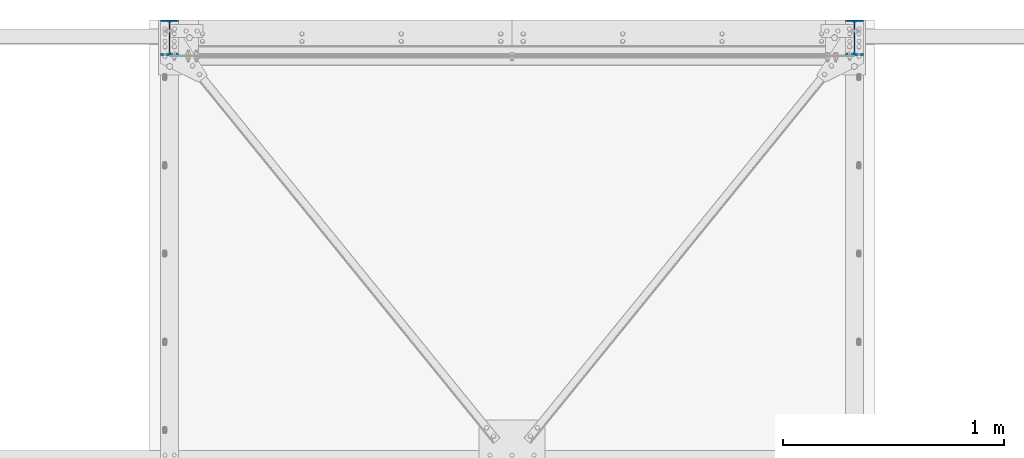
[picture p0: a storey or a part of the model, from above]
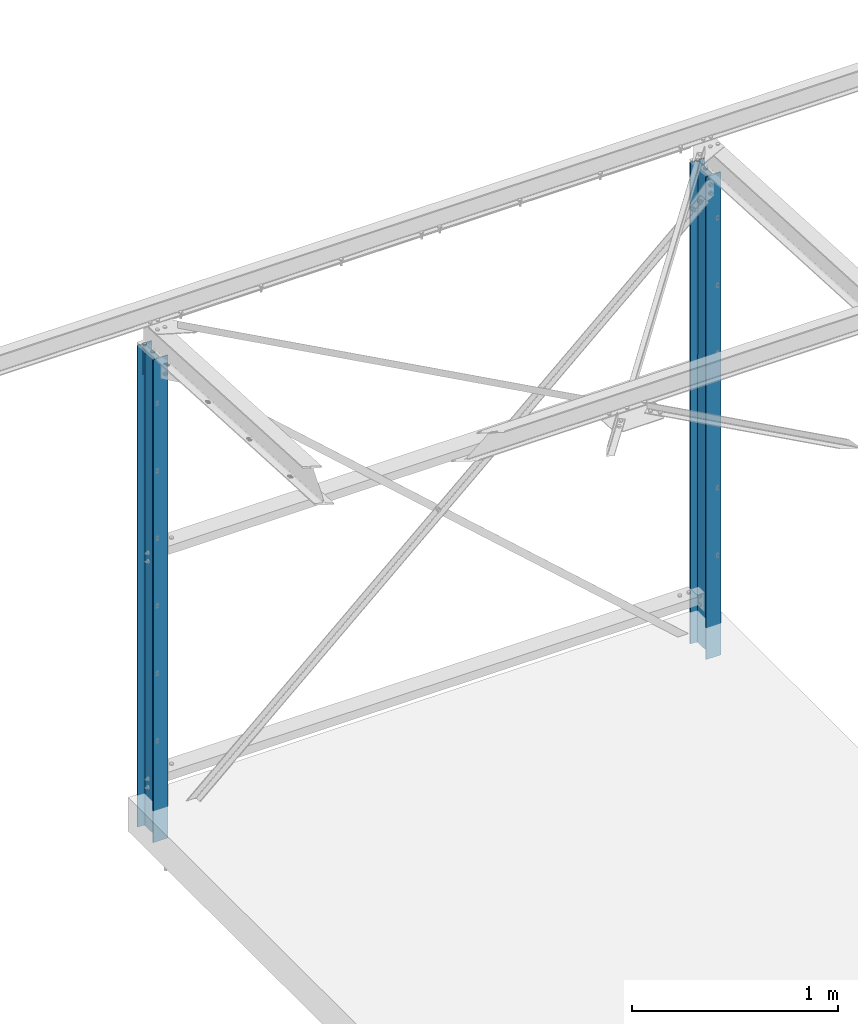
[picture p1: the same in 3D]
Properties of the parts of a building model (IFC2X3)

# File
Description: ViewDefinition[CoordinationView_V2.0, QuantityTakeOffAddOnView], Option [BaseQuantities:On], Option [GridExport:Off], Option [Assemblies:On], Option [Bolts:On], Option [Rebars:On], Option [PourObjects:Off], Option [Welds:Off], Option [SurfaceTreatments:Off], Option [LocationBy:0], Option [ViewColors:On], Option [SectionedSpine:Off], Option [PropertySets:On], Option [Export all:Off]
File name: preau_poleaero.ifc
Time: 2021-06-01T16:35:58
Author: PORTCM01\professeur
Organization: Structural Designer
Written by: IFC Database Version: Work
Made in: Tekla Structures Educational 2019, IFC Export Version: 4.0.0.0 Mar 7 2019

# IfcSite, Undefined
RefElevation: 0 mm

# IfcBuildingStorey, Undefined
In: Undefined
Elevation: 0 mm

# IfcBeam: 4550*200 (2)
In: Undefined
Description: 4550*200; Material: CONCRETE/C25/30
Tekla Commun - Phase: 1; Profil: 4550*200; Nom: POUTRE; sets with these values: 2
Tekla Quantités - Hauteur: 4550 mm; Largeur: 200 mm; sets with these values: 2
Pset_BeamCommon - LoadBearing: no
Name | Repère de pièce = Repère d'assemblage = Reference | Poids (kg) = NetWeight (kg) | Volume (m3) | Surface supérieure totale (m2) | Surface par tonne (m2) | Surface nette (m2) | Longueur (mm) | Length (mm) | OuterSurfaceArea (m2) | NetVolume (m3)
POUTRE | Po5 | 29791.9 | 12.4 | 2.7 | 4.4 | 131.7 | 13733.4 | 13733.4 | 131.739 | 12.4133
POUTRE | Po4 | 20476.6 | 8.5 | 1.9 | 4.5 | 91.2 | 9478.7 | 9478.66 | 91.2034 | 8.53192

# IfcBeam: 8550*200 (4)
In: Undefined
Description: 8550*200; Material: CONCRETE/C25/30
Tekla Commun - Phase: 1; Profil: 8550*200; Nom: POUTRE; sets with these values: 2
Tekla Quantités - Surface par tonne: 4.4 m2; Hauteur: 8550 mm; Largeur: 200 mm; sets with these values: 2
Pset_BeamCommon - LoadBearing: no
Name | Repère de pièce = Repère d'assemblage = Reference | Poids (kg) = NetWeight (kg) | Volume (m3) | Surface supérieure totale (m2) | Surface nette (m2) | Longueur (mm) = Length (mm) | OuterSurfaceArea (m2) | NetVolume (m3)
POUTRE | Po7 | 37962 | 15.8 | 1.9 | 165.3 | 9250 | 165.295 | 15.8175
POUTRE | Po6 | 38372.4 | 16 | 1.9 | 167.8 | 9450 | 167.753 | 15.9885
POUTRE | Po3 | 124128 | 51.7 | 6.9 | 547.8 | 34778 | 547.813 | 51.7201
POUTRE | Po2 | 38782.8 | 16.2 | 1.9 | 170.2 | 9650 | 170.212 | 16.1595

# IfcBeam: IPE120 (3)
In: Undefined
Description: IPE120; Material: Undefined/S275-E28
Tekla Commun - Finition: GALVA; Phase: 2; Profil: IPE120; Nom: PANNE; sets with these values: 2
Tekla Quantités - Poids: 0 kg; Volume: 0 m3; Surface supérieure totale: 0 m2; Surface par tonne: 0 m2; Surface nette: 5.2 m2; Hauteur: 120 mm; Largeur: 64 mm; Longueur: 10758 mm; sets with these values: 2
Pset_BeamCommon - LoadBearing: no
BaseQuantities - Length: 10758 mm; OuterSurfaceArea: 5.11005 m2; NetVolume: 0.0137591 m3; NetWeight: 0 kg
Name | Repère de pièce = Repère d'assemblage = Reference
PANNE | PN37
PANNE | PN36
PANNE | PN11

# IfcBeam: IPE160 (4)
In: Undefined
Description: IPE160; Material: Undefined/S275-E28
Tekla Commun - Finition: GALVA; Phase: 2; Profil: IPE160; Nom: TRAVERSE; sets with these values: 2
Tekla Quantités - Poids: 0 kg; Volume: 0 m3; Surface supérieure totale: 0 m2; Surface par tonne: 0 m2; Surface nette: 2.6 m2; Hauteur: 160 mm; Largeur: 82 mm; Longueur: 4043.9 mm; sets with these values: 2
Pset_BeamCommon - LoadBearing: no
BaseQuantities - Length: 4043.91 mm; OuterSurfaceArea: 2.51935 m2; NetVolume: 0.0078273 m3; NetWeight: 0 kg
Name | Repère de pièce = Repère d'assemblage = Reference
2 x TRAVERSE | T8
TRAVERSE | T6
TRAVERSE | T9

# IfcBeam: L40*4 (4)
In: Undefined
Description: L40*4; Material: Undefined/S235-E24
Tekla Commun - Finition: GALVA; Repère de pièce: S15; Repère d'assemblage: S15; Phase: 2; Profil: L40*4; Nom: STABILITE CVT; sets with these values: 2
Tekla Quantités - Poids: 0 kg; Volume: 0 m3; Surface supérieure totale: 0 m2; Surface par tonne: 0 m2; Surface nette: 0.4 m2; Hauteur: 40 mm; Largeur: 40 mm; Longueur: 2209.6 mm; sets with these values: 2
Pset_BeamCommon - LoadBearing: no; Reference: S15
BaseQuantities - Length: 2209.65 mm; OuterSurfaceArea: 0.342495 m2; NetVolume: 0.000672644 m3; NetWeight: 0 kg

# IfcBeam: PL1*20000 (2)
In: Undefined
Description: PL1*20000; Material: Undefined/S235-E24
Tekla Commun - Repère de pièce: X1; Repère d'assemblage: X1; Phase: 2; Profil: PL1*20000; Nom: BAVETTE; sets with these values: 2
Tekla Quantités - Poids: 0 kg; Volume: 0 m3; Surface supérieure totale: 0 m2; Surface par tonne: 0 m2; Surface nette: 7 m2; Hauteur: 20000 mm; Largeur: 1 mm; Longueur: 167.9 mm; sets with these values: 2
Pset_BeamCommon - LoadBearing: no; Reference: X1
BaseQuantities - Length: 167.904 mm; OuterSurfaceArea: 7.03146 m2; NetVolume: 0.00349555 m3; NetWeight: 0 kg

# IfcBeam: PL10*141 (2)
In: Undefined
Description: PL10*141; Material: Undefined/S235-E24
Tekla Commun - Finition: GALVA; Repère de pièce: 496; Repère d'assemblage: G11; Phase: 2; Profil: PL10*141; Nom: GOUSSET; sets with these values: 2
Tekla Quantités - Poids: 0 kg; Volume: 0 m3; Surface supérieure totale: 0 m2; Surface par tonne: 0 m2; Surface nette: 0.2 m2; Hauteur: 141.2 mm; Largeur: 10 mm; Longueur: 732.8 mm; sets with these values: 2
Pset_BeamCommon - LoadBearing: no; Reference: 496
BaseQuantities - Length: 732.76 mm; OuterSurfaceArea: 0.167426 m2; NetVolume: 0.000757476 m3; NetWeight: 0 kg

# IfcBeam: PL10*160 (6)
In: Undefined
Description: PL10*160; Material: Undefined/S275-E28
Tekla Commun - Finition: GALVA; Repère de pièce: 500; Phase: 2; Profil: PL10*160; Nom: PLATINE; sets with these values: 2
Tekla Quantités - Poids: 0 kg; Volume: 0 m3; Surface supérieure totale: 0 m2; Surface par tonne: 0 m2; Surface nette: 0.1 m2; Hauteur: 160 mm; Largeur: 10 mm; Longueur: 250 mm; sets with these values: 2
Pset_BeamCommon - LoadBearing: no; Reference: 500
BaseQuantities - Length: 250 mm; OuterSurfaceArea: 0.0882 m2; NetVolume: 0.0004 m3; NetWeight: 0 kg
Name | Repère d'assemblage
4 x PLATINE | G29
2 x PLATINE | G28

# IfcBeam: PL10*360 (4)
In: Undefined
Description: PL10*360; Material: Undefined/S235-E24
Tekla Commun - Finition: GALVA; Repère de pièce: 499; Repère d'assemblage: G29; Phase: 2; Profil: PL10*360; Nom: GOUSSET; sets with these values: 2
Tekla Quantités - Poids: 0 kg; Volume: 0 m3; Surface supérieure totale: 0 m2; Surface par tonne: 0 m2; Surface nette: 0.1 m2; Hauteur: 360 mm; Largeur: 10 mm; Longueur: 237.4 mm; sets with these values: 2
Pset_BeamCommon - LoadBearing: no; Reference: 499
BaseQuantities - Length: 237.448 mm; OuterSurfaceArea: 0.115218 m2; NetVolume: 0.000519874 m3; NetWeight: 0 kg

# IfcBeam: PL10*370 (2)
In: Undefined
Description: PL10*370; Material: Undefined/S235-E24
Tekla Commun - Finition: GALVA; Repère de pièce: 497; Repère d'assemblage: G28; Phase: 2; Profil: PL10*370; Nom: GOUSSET; sets with these values: 2
Tekla Quantités - Poids: 0 kg; Volume: 0 m3; Surface supérieure totale: 0 m2; Surface par tonne: 0 m2; Surface nette: 0.1 m2; Hauteur: 370 mm; Largeur: 10 mm; Longueur: 309.4 mm; sets with these values: 2
Pset_BeamCommon - LoadBearing: no; Reference: 497
BaseQuantities - Length: 309.388 mm; OuterSurfaceArea: 0.14183 m2; NetVolume: 0.000653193 m3; NetWeight: 0 kg

# IfcBeam: PL10*80 (4)
In: Undefined
Description: PL10*80; Material: Undefined/S235-E24
Tekla Commun - Finition: GALVA; Repère de pièce: 498; Repère d'assemblage: B14; Phase: 2; Profil: PL10*80; Nom: GOUSSET; sets with these values: 2
Tekla Quantités - Poids: 0 kg; Volume: 0 m3; Surface supérieure totale: 0 m2; Surface par tonne: 0 m2; Surface nette: 0 m2; Hauteur: 80 mm; Largeur: 10 mm; Longueur: 260 mm; sets with these values: 2
Pset_BeamCommon - LoadBearing: no; Reference: 498
BaseQuantities - Length: 260 mm; OuterSurfaceArea: 0.0466612 m2; NetVolume: 0.00020103 m3; NetWeight: 0 kg

# IfcBeam: PL10*82 (4)
In: Undefined
Description: PL10*82
Tekla Commun - Finition: GALVA; Phase: 2; Profil: PL10*82; sets with these values: 2
Tekla Quantités - Poids: 0 kg; Volume: 0 m3; Surface supérieure totale: 0 m2; Surface par tonne: 0 m2; Hauteur: 82 mm; Largeur: 10 mm; sets with these values: 2
Pset_BeamCommon - LoadBearing: no
BaseQuantities - NetWeight: 0 kg
Name | Material | Repère de pièce = Reference | Repère d'assemblage | Nom | Surface nette (m2) | Longueur (mm) | Length (mm) | OuterSurfaceArea (m2) | NetVolume (m3)
PLAT | Undefined/S235-E24 | 502 | PT11 | PLAT | 0 | 150 | 149.999 | 0.0297919 | 0.000125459
PLAT | Undefined/S235-E24 | 502 | PT13 | PLAT | 0 | 150 | 149.999 | 0.0297919 | 0.000125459
2 x PLATINE | Undefined/S275-E28 | 501 | G11 | PLATINE | 0.1 | 300 | 300 | 0.05684 | 0.000246

# IfcBeam: PL3*1450 (2)
In: Undefined
Description: PL3*1450; Material: Undefined/S235-E24
Tekla Commun - Finition: GALVA; Repère de pièce: F18; Repère d'assemblage: F18; Phase: 2; Profil: PL3*1450; Nom: FEUILLURE; sets with these values: 2
Tekla Quantités - Poids: 0 kg; Volume: 0 m3; Surface supérieure totale: 0 m2; Surface par tonne: 0 m2; Surface nette: 0.5 m2; Hauteur: 1450 mm; Largeur: 3 mm; Longueur: 159.3 mm; sets with these values: 2
Pset_BeamCommon - LoadBearing: no; Reference: F18
BaseQuantities - Length: 159.306 mm; OuterSurfaceArea: 0.479917 m2; NetVolume: 0.000705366 m3; NetWeight: 0 kg

# IfcBeam: PL5*157 (4)
In: Undefined
Description: PL5*157; Material: Undefined/S235-E24
Tekla Commun - Finition: GALVA; Repère de pièce: G32; Repère d'assemblage: G32; Phase: 2; Profil: PL5*157; Nom: GOUSSET; sets with these values: 2
Tekla Quantités - Poids: 0 kg; Volume: 0 m3; Surface supérieure totale: 0 m2; Surface par tonne: 0 m2; Surface nette: 0 m2; Hauteur: 156.7 mm; Largeur: 5 mm; Longueur: 169 mm; sets with these values: 2
Pset_BeamCommon - LoadBearing: no; Reference: G32
BaseQuantities - Length: 168.971 mm; NetWeight: 0 kg
Name | OuterSurfaceArea (m2) | NetVolume (m3)
GOUSSET | 0.0305038 | 0.000069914
GOUSSET | 0.030501 | 0.0000699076
2 x GOUSSET | 0.0305038 | 0.0000699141

# IfcBeam: PL5*211 (4)
In: Undefined
Description: PL5*211; Material: Undefined/S235-E24
Tekla Commun - Finition: GALVA; Repère de pièce: G30; Repère d'assemblage: G30; Phase: 2; Profil: PL5*211; Nom: GOUSSET; sets with these values: 2
Tekla Quantités - Poids: 0 kg; Volume: 0 m3; Surface supérieure totale: 0 m2; Surface par tonne: 0 m2; Surface nette: 0.1 m2; Hauteur: 211.5 mm; Largeur: 5 mm; Longueur: 235.8 mm; sets with these values: 2
Pset_BeamCommon - LoadBearing: no; Reference: G30
BaseQuantities - NetVolume: 0.000143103 m3; NetWeight: 0 kg
Name | Length (mm) | OuterSurfaceArea (m2)
GOUSSET | 235.796 | 0.0608244
GOUSSET | 235.796 | 0.0608243
2 x GOUSSET | 235.797 | 0.0608245

# IfcBeam: PL5*300, GOUSSET
In: Undefined
Description: PL5*300; Material: Undefined/S235-E24
Tekla Commun - Finition: GALVA; Repère de pièce: G31; Repère d'assemblage: G31; Phase: 2; Profil: PL5*300; Nom: GOUSSET; sets with these values: 2
Tekla Quantités - Poids: 0 kg; Volume: 0 m3; Surface supérieure totale: 0 m2; Surface par tonne: 0 m2; Surface nette: 0.2 m2; Hauteur: 300.3 mm; Largeur: 5 mm; Longueur: 353.7 mm; sets with these values: 2
Pset_BeamCommon - LoadBearing: no; Reference: G31
BaseQuantities - Length: 353.658 mm; OuterSurfaceArea: 0.213616 m2; NetVolume: 0.000518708 m3; NetWeight: 0 kg

# IfcBeam: PL5*60 (4)
In: Undefined
Description: PL5*60; Material: Undefined/S235-E24
Tekla Commun - Finition: GALVA; Repère de pièce: A16; Repère d'assemblage: A16; Phase: 2; Profil: PL5*60; Nom: ATTACHE; sets with these values: 2
Tekla Quantités - Poids: 0 kg; Volume: 0 m3; Surface supérieure totale: 0 m2; Surface par tonne: 0 m2; Surface nette: 0 m2; Hauteur: 60 mm; Largeur: 5 mm; Longueur: 247 mm; sets with these values: 2
Pset_BeamCommon - LoadBearing: no; Reference: A16
BaseQuantities - Length: 247 mm; OuterSurfaceArea: 0.03336 m2; NetVolume: 0.0000756 m3; NetWeight: 0 kg

# IfcBeam: TOLE10*180 (2)
In: Undefined
Description: TOLE10*180; Material: Undefined/S235-E24
Tekla Commun - Repère de pièce: 362; Phase: 2; Profil: TOLE10*180; Nom: PLATINE; sets with these values: 2
Tekla Quantités - Poids: 0 kg; Volume: 0 m3; Surface supérieure totale: 0 m2; Surface par tonne: 0 m2; Surface nette: 0.1 m2; Hauteur: 180 mm; Largeur: 10 mm; Longueur: 250 mm; sets with these values: 2
Pset_BeamCommon - LoadBearing: no; Reference: 362
BaseQuantities - Length: 250 mm; OuterSurfaceArea: 0.0909042 m2; NetVolume: 0.000414 m3; NetWeight: 0 kg
Name | Repère d'assemblage
PLATINE | PT13
PLATINE | PT11

# IfcBeam: UPF-100*50*4 (2)
In: Undefined
Description: UPF-100*50*4; Material: Undefined/S235-E24
Tekla Commun - Finition: GALVA; Repère de pièce: L31; Repère d'assemblage: L31; Phase: 2; Profil: UPF-100*50*4; Nom: LISSE; sets with these values: 2
Tekla Quantités - Poids: 0 kg; Volume: 0 m3; Surface supérieure totale: 0.3 m2; Surface par tonne: 0 m2; Surface nette: 1.2 m2; Hauteur: 100 mm; Largeur: 50 mm; Longueur: 3000 mm; sets with these values: 2
Pset_BeamCommon - LoadBearing: no; Reference: L31
BaseQuantities - Length: 3000 mm; OuterSurfaceArea: 1.17754 m2; NetVolume: 0.002304 m3; NetWeight: 0 kg

# IfcColumn: IPE160 (2)
In: Undefined
Description: IPE160; Material: Undefined/S275-E28
Tekla Commun - Finition: GALVA; Phase: 2; Profil: IPE160; Nom: POTEAU; sets with these values: 2
Tekla Quantités - Poids: 0 kg; Volume: 0 m3; Surface supérieure totale: 0 m2; Surface par tonne: 0 m2; Surface nette: 1.8 m2; Hauteur: 160 mm; Largeur: 82 mm; Longueur: 2862 mm; sets with these values: 2
Pset_ColumnCommon - LoadBearing: no
BaseQuantities - Length: 2861.96 mm; OuterSurfaceArea: 1.783 m2; NetVolume: 0.00554292 m3; NetWeight: 0 kg
Name | Repère de pièce = Reference | Repère d'assemblage
POTEAU | 131 | PT13
POTEAU | 194 | PT11

# IfcElementAssembly (55)
In: Undefined
Tekla Assemblages - sets with these values: 2
Name | Poids Assemblage/Elément béton (kg) | Nom Assemblage/Elément béton | Repère Assemblage/Elément béton | Width (mm)
2 x BAVETTE | 0 | BAVETTE | X1 | 43.7883
4 x GOUSSET | 0 | GOUSSET | G32 | 5
4 x ATTACHE | 0 | ATTACHE | A16 | 147
POTEAU | 0 | POTEAU | PT11 | 180
POTEAU | 0 | POTEAU | PT13 | 180
GOUSSET | 0 | GOUSSET | G31 | 5
4 x GOUSSET | 0 | GOUSSET | G30 | 5
4 x STABILITE CVT | 0 | STABILITE CVT | S15 | 40
4 x GOUSSET | 0 | GOUSSET | G29 | 160
2 x GOUSSET | 0 | GOUSSET | G11 | 82
2 x GOUSSET | 0 | GOUSSET | G28 | 160
2 x BUTON | 0 | BUTON | B14 | 80
DALLE | 22200 | DALLE | Da8 | 200 | PredefinedType: REINFORCEMENT_UNIT; Tekla Assemblages - Poids ferraillage Elément béton: 0 kg
DALLE | 233208 | DALLE | Da6 | 200 | PredefinedType: REINFORCEMENT_UNIT; Tekla Assemblages - Poids ferraillage Elément béton: 0 kg
DALLE | 148983 | DALLE | Da9 | 230 | PredefinedType: REINFORCEMENT_UNIT; Tekla Assemblages - Poids ferraillage Elément béton: 0 kg
POUTRE | 37962 | POUTRE | Po7 | 200 | PredefinedType: REINFORCEMENT_UNIT; Tekla Assemblages - Poids ferraillage Elément béton: 0 kg
POUTRE | 38372.4 | POUTRE | Po6 | 200 | PredefinedType: REINFORCEMENT_UNIT; Tekla Assemblages - Poids ferraillage Elément béton: 0 kg
POUTRE | 29791.9 | POUTRE | Po5 | 200 | PredefinedType: REINFORCEMENT_UNIT; Tekla Assemblages - Poids ferraillage Elément béton: 0 kg
DALLE | 142505 | DALLE | Da5 | 220 | PredefinedType: REINFORCEMENT_UNIT; Tekla Assemblages - Poids ferraillage Elément béton: 0 kg
DALLE | 71045.8 | DALLE | Da4 | 230 | PredefinedType: REINFORCEMENT_UNIT; Tekla Assemblages - Poids ferraillage Elément béton: 0 kg
2 x FEUILLURE | 0 | FEUILLURE | F18 | 50.0885
2 x STABILTE | 0 | STABILTE | S14 | 40
2 x LISSE | 0 | LISSE | L31 | 50
2 x TRAVERSE | 0 | TRAVERSE | T8 | 82
TRAVERSE | 0 | TRAVERSE | T6 | 82
PANNE | 0 | PANNE | PN37 | 64
PANNE | 0 | PANNE | PN36 | 64
PANNE | 0 | PANNE | PN11 | 64
TRAVERSE | 0 | TRAVERSE | T9 | 82
POUTRE | 20476.6 | POUTRE | Po4 | 200 | PredefinedType: REINFORCEMENT_UNIT; Tekla Assemblages - Poids ferraillage Elément béton: 0 kg
POUTRE | 124128 | POUTRE | Po3 | 200 | PredefinedType: REINFORCEMENT_UNIT; Tekla Assemblages - Poids ferraillage Elément béton: 0 kg
POUTRE | 38782.8 | POUTRE | Po2 | 200 | PredefinedType: REINFORCEMENT_UNIT; Tekla Assemblages - Poids ferraillage Elément béton: 0 kg

# IfcMechanicalFastener: Bolt assembly (82)
In: Undefined
Tekla Boulons - sets with these values: 2
Name | NominalDiameter (mm) | NominalLength (mm) = Longueur (mm) | Material = Standard | Diamètre (mm)
4 x Bolt assembly | 12 | 7.4 | #_SB-8.8-ZINGUE | 14
25 x Bolt assembly | 12 | 30 | 8.8-SB-GALVA | 12
19 x Bolt assembly | 10 | 30 | 6.8 | 10 | Tekla Boulons - Nom: Boulons tête H
24 x Bolt assembly | 12 | 40 | 8.8-SB-GALVA | 12
6 x Bolt assembly | 12 | 89.2 | HILTI-HSA-R | 12
4 x Bolt assembly | 16 | 146.2 | HILTI-HST-R | 16

# IfcMember: L40*4 (2)
In: Undefined
Description: L40*4; Material: Undefined/S235-E24
Tekla Commun - Finition: GALVA; Repère de pièce: S14; Repère d'assemblage: S14; Phase: 2; Profil: L40*4; Nom: STABILTE; sets with these values: 2
Tekla Quantités - Poids: 0 kg; Volume: 0 m3; Surface supérieure totale: 0 m2; Surface par tonne: 0 m2; Surface nette: 0.6 m2; Hauteur: 40 mm; Largeur: 40 mm; Longueur: 3982 mm; sets with these values: 2
Pset_MemberCommon - LoadBearing: no; Reference: S14
BaseQuantities - Length: 3982 mm; OuterSurfaceArea: 0.61721 m2; GrossSurfaceArea: 0.61721 m2; CrossSectionArea: 0.000308 m2; NetVolume: 0.00121136 m3; GrossVolume: 0.00122646 m3; NetWeight: 0 kg; GrossWeight: 0 kg

# IfcMember: TUBE-60.3*3.2 (2)
In: Undefined
Description: TUBE-60.3*3.2; Material: Undefined/S235-E24
Tekla Commun - Finition: GALVA; Repère de pièce: 196; Repère d'assemblage: B14; Phase: 2; Profil: TUBE-60.3*3.2; Nom: BUTON; sets with these values: 2
Tekla Quantités - Poids: 0 kg; Volume: 0 m3; Surface supérieure totale: 0 m2; Surface par tonne: 0 m2; Surface nette: 0.4 m2; Hauteur: 60.3 mm; Largeur: 60.3 mm; Longueur: 2230 mm; sets with these values: 2
Pset_MemberCommon - LoadBearing: no; Reference: 196
BaseQuantities - Length: 2230 mm; OuterSurfaceArea: 0.417322 m2; GrossSurfaceArea: 0 m2; CrossSectionArea: 0.000574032 m2; NetVolume: 0.00123369 m3; GrossVolume: 0.00128009 m3; NetWeight: 0 kg; GrossWeight: 0 kg

# IfcSlab: 200*13930, DALLE
In: Undefined
Description: 200*13930; PredefinedType: FLOOR; Material: CONCRETE/C25/30
Tekla Commun - Repère de pièce: Da6; Repère d'assemblage: Da6; Phase: 1; Profil: 200*13930; Nom: DALLE; sets with these values: 2
Tekla Quantités - Poids: 233208 kg; Volume: 97.2 m3; Surface supérieure totale: 485.8 m2; Surface par tonne: 4.3 m2; Surface nette: 996.8 m2; Hauteur: 13930 mm; Largeur: 200 mm; Longueur: 49248 mm; sets with these values: 2
Pset_SlabCommon - LoadBearing: no; Reference: Da6
BaseQuantities - Width: 200 mm; NetVolume: 97.1699 m3; NetArea: 485.85 m2; NetWeight: 233208 kg

# IfcSlab: 200*5000, DALLE
In: Undefined
Description: 200*5000; PredefinedType: FLOOR; Material: CONCRETE/C25/30
Tekla Commun - Repère de pièce: Da8; Repère d'assemblage: Da8; Phase: 1; Profil: 200*5000; Nom: DALLE; sets with these values: 2
Tekla Quantités - Poids: 22200 kg; Volume: 9.2 m3; Surface supérieure totale: 46.2 m2; Surface par tonne: 4.4 m2; Surface nette: 98.2 m2; Hauteur: 5000 mm; Largeur: 200 mm; Longueur: 9250 mm; sets with these values: 2
Pset_SlabCommon - LoadBearing: no; Reference: Da8
BaseQuantities - Width: 200 mm; NetVolume: 9.25 m3; NetArea: 46.25 m2; NetWeight: 22200 kg

# IfcSlab: 220*9250, DALLE
In: Undefined
Description: 220*9250; PredefinedType: FLOOR; Material: CONCRETE/C25/30
Tekla Commun - Repère de pièce: Da5; Repère d'assemblage: Da5; Phase: 1; Profil: 220*9250; Nom: DALLE; sets with these values: 2
Tekla Quantités - Poids: 142505 kg; Volume: 59.4 m3; Surface supérieure totale: 269.9 m2; Surface par tonne: 3.9 m2; Surface nette: 556.7 m2; Hauteur: 9250 mm; Largeur: 220 mm; Longueur: 29178 mm; sets with these values: 2
Pset_SlabCommon - LoadBearing: no; Reference: Da5
BaseQuantities - Width: 220 mm; NetVolume: 59.3772 m3; NetArea: 269.897 m2; NetWeight: 142505 kg

# IfcSlab: 230*9250 (2)
In: Undefined
Description: 230*9250; PredefinedType: FLOOR; Material: CONCRETE/C25/30
Tekla Commun - Phase: 1; Profil: 230*9250; Nom: DALLE; sets with these values: 2
Tekla Quantités - Hauteur: 9250 mm; Largeur: 230 mm; sets with these values: 2
Pset_SlabCommon - LoadBearing: no
BaseQuantities - Width: 230 mm
Name | Repère de pièce = Repère d'assemblage = Reference | Poids (kg) = NetWeight (kg) | Volume (m3) | Surface supérieure totale (m2) | Surface par tonne (m2) | Surface nette (m2) | Longueur (mm) | NetVolume (m3) | NetArea (m2)
DALLE | Da9 | 148983 | 62.1 | 269.9 | 3.7 | 557.5 | 29178 | 62.0762 | 269.897
DALLE | Da4 | 71045.8 | 29.6 | 128.7 | 3.8 | 268.1 | 14279.8 | 29.6024 | 128.706
